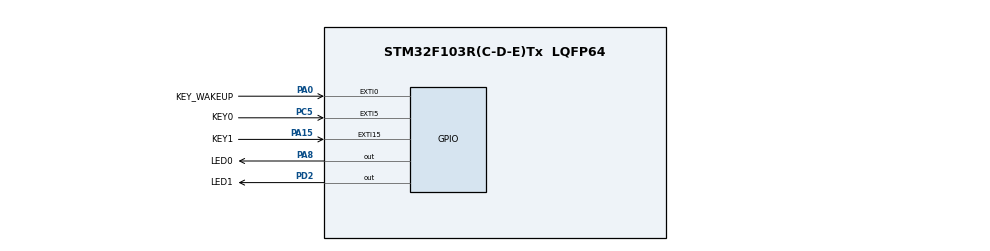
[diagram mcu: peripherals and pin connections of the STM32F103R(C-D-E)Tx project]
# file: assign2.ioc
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Mcu.Family=STM32F1
Mcu.Name=STM32F103R(C-D-E)Tx
Mcu.Package=LQFP64
NVIC.EXTI0_IRQn=true\:1\:0\:true\:false\:true\:true\:true\:true
NVIC.EXTI15_10_IRQn=true\:1\:2\:true\:false\:true\:true\:true\:true
NVIC.EXTI9_5_IRQn=true\:1\:1\:true\:false\:true\:true\:true\:true
NVIC.PriorityGroup=NVIC_PRIORITYGROUP_2
PA0-WKUP.GPIO_Label=KEY_WAKEUP
PA0-WKUP.GPIO_PuPd=GPIO_PULLDOWN
PA0-WKUP.Signal=GPXTI0
PA13.Mode=Serial_Wire
PA13.Signal=SYS_JTMS-SWDIO
PA14.Mode=Serial_Wire
PA14.Signal=SYS_JTCK-SWCLK
PA15.GPIO_Label=KEY1
PA15.GPIO_ModeDefaultEXTI=GPIO_MODE_IT_FALLING
PA15.GPIO_PuPd=GPIO_PULLUP
PA15.Signal=GPXTI15
PA8.GPIO_Label=LED0
PA8.GPIO_Speed=GPIO_SPEED_FREQ_HIGH
PA8.Signal=GPIO_Output
PC5.GPIO_Label=KEY0
PC5.GPIO_ModeDefaultEXTI=GPIO_MODE_IT_FALLING
PC5.GPIO_PuPd=GPIO_PULLUP
PC5.Signal=GPXTI5
PD0-OSC_IN.Mode=HSE-External-Oscillator
PD0-OSC_IN.Signal=RCC_OSC_IN
PD1-OSC_OUT.Mode=HSE-External-Oscillator
PD1-OSC_OUT.Signal=RCC_OSC_OUT
PD2.GPIO_Label=LED1
PD2.GPIO_Speed=GPIO_SPEED_FREQ_HIGH
PD2.Signal=GPIO_Output
ProjectManager.HeapSize=0x200
ProjectManager.StackSize=0x400
ProjectManager.TargetToolchain=CMake
RCC.AHBFreq_Value=64000000
RCC.APB1CLKDivider=RCC_HCLK_DIV2
RCC.APB1Freq_Value=32000000
RCC.APB1TimFreq_Value=64000000
RCC.APB2CLKDivider=RCC_HCLK_DIV2
RCC.APB2Freq_Value=32000000
RCC.APB2TimFreq_Value=64000000
RCC.HCLKFreq_Value=64000000
RCC.PLLMUL=RCC_PLL_MUL8
RCC.PLLSourceVirtual=RCC_PLLSOURCE_HSE
RCC.SYSCLKFreq_VALUE=64000000
RCC.SYSCLKSource=RCC_SYSCLKSOURCE_PLLCLK
RCC.USBFreq_Value=64000000
board=custom

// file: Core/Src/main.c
/* USER CODE BEGIN Header */
/**
 ******************************************************************************
 * @file           : main.c
 * @brief          : Main program body
 ******************************************************************************
 * @attention
 *
 * Copyright (c) 2024 STMicroelectronics.
 * All rights reserved.
 *
 * This software is licensed under terms that can be found in the LICENSE file
 * in the root directory of this software component.
 * If no LICENSE file comes with this software, it is provided AS-IS.
 *
 ******************************************************************************
 */
/* USER CODE END Header */
#include "main.h"

#include "gpio.h"
/* USER CODE BEGIN Includes */
#include "hamming.h"
#include "lcd.h"
/* USER CODE END Includes */

/* USER CODE BEGIN PV */
volatile uint8_t main_status = ENCODE;
volatile uint8_t flag_LCDclean = 0;
HammingMessage hammingMsg = {0, 0, 0, 0};
/* USER CODE END PV */

void SystemClock_Config(void);

int main(void) {

  /* MCU Configuration--------------------------------------------------------*/

  /* Reset of all peripherals, Initializes the Flash interface and the Systick. */
  HAL_Init();

  /* Configure the system clock */
  SystemClock_Config();

  /* USER CODE BEGIN SysInit */
  LCD_Init();
  uint8_t msgOriginal[23] = "Original Message: ";
  uint8_t msgEncoded[22] = "Hamming Code: ";
  uint8_t msgDecoded[22] = "Decoded Message: ";
  uint8_t parityInfo[15] = "Error in bit ";
  uint8_t *statusString[] = {(uint8_t *)"ENCODING MODE", (uint8_t *)"DECODING MODE"};
  /* USER CODE END SysInit */

  /* Initialize all configured peripherals */
  MX_GPIO_Init();

  /* Infinite loop */
  /* USER CODE BEGIN WHILE */
  LCD_Clear(WHITE);
  BACK_COLOR = WHITE;
  POINT_COLOR = BLACK;
  while (1) {
    if (flag_LCDclean == DIRTY) {
      LCD_Clear(WHITE);
      flag_LCDclean = CLEAN;
    }
    /* USER CODE END WHILE */

    /* USER CODE BEGIN 3 */
    LCD_ShowString(48, 10, 200, 24, 24, statusString[main_status]);
    if (main_status == ENCODE) {
      uintToBinString(hammingMsg.message, 18, 22, msgOriginal);
      uintToBinString(hammingMsg.encoded, 14, 21, msgEncoded);
      LCD_ShowString(10, 40, 200, 12, 12, msgOriginal);
      LCD_ShowString(10, 70, 200, 12, 12, msgEncoded);
    } else if (main_status == DECODE) {
      uintToBinString(hammingMsg.encoded, 14, 21, msgEncoded);
      uintToBinString(hammingMsg.message, 17, 21, msgDecoded);
      LCD_ShowString(10, 40, 200, 12, 12, msgEncoded);
      LCD_ShowString(10, 70, 200, 12, 12, msgDecoded);
      if (hammingMsg.parity) {
        parityInfo[13] = '0' + hammingMsg.parity;
        LCD_ShowString(10, 100, 200, 12, 12, parityInfo);
      } else {
        LCD_ShowString(10, 100, 200, 12, 12, (uint8_t *)"No error detected");
      }
    }
    /* USER CODE END 3 */
  }
}

void SystemClock_Config(void) {
  RCC_OscInitTypeDef RCC_OscInitStruct = {0};
  RCC_ClkInitTypeDef RCC_ClkInitStruct = {0};

  /** Initializes the RCC Oscillators according to the specified parameters
   * in the RCC_OscInitTypeDef structure.
   */
  RCC_OscInitStruct.OscillatorType = RCC_OSCILLATORTYPE_HSE;
  RCC_OscInitStruct.HSEState = RCC_HSE_ON;
  RCC_OscInitStruct.HSEPredivValue = RCC_HSE_PREDIV_DIV1;
  RCC_OscInitStruct.HSIState = RCC_HSI_ON;
  RCC_OscInitStruct.PLL.PLLState = RCC_PLL_ON;
  RCC_OscInitStruct.PLL.PLLSource = RCC_PLLSOURCE_HSE;
  RCC_OscInitStruct.PLL.PLLMUL = RCC_PLL_MUL2;
  if (HAL_RCC_OscConfig(&RCC_OscInitStruct) != HAL_OK) {
    Error_Handler();
  }

  /** Initializes the CPU, AHB and APB buses clocks
   */
  RCC_ClkInitStruct.ClockType = RCC_CLOCKTYPE_HCLK | RCC_CLOCKTYPE_SYSCLK | RCC_CLOCKTYPE_PCLK1 | RCC_CLOCKTYPE_PCLK2;
  RCC_ClkInitStruct.SYSCLKSource = RCC_SYSCLKSOURCE_PLLCLK;
  RCC_ClkInitStruct.AHBCLKDivider = RCC_SYSCLK_DIV1;
  RCC_ClkInitStruct.APB1CLKDivider = RCC_HCLK_DIV1;
  RCC_ClkInitStruct.APB2CLKDivider = RCC_HCLK_DIV1;

  if (HAL_RCC_ClockConfig(&RCC_ClkInitStruct, FLASH_LATENCY_0) != HAL_OK) {
    Error_Handler();
  }
}

void Error_Handler(void) {
  __disable_irq();
  while (1) {
  }
}
